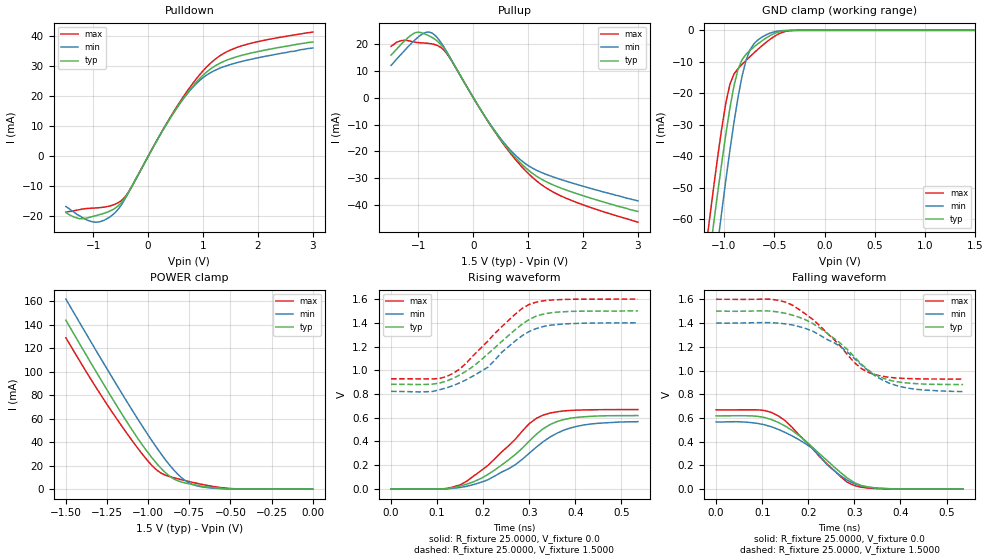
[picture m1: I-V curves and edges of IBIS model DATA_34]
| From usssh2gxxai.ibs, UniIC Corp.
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|When TDQS is enabled, NU_TDQS is a output with terminal resistance;
|When TDQS is disabled, NU_TDQS is a DM;
|   Model DATA_34
[Model]  DATA_34
Model_type I/O
Polarity   Non-Inverting
Enable   Active-High
Vinl =   0.61500000V
Vinh =   0.88500000V
Vmeas =   0.750000000V
Rref =   25.00000000
Vref =   0.75000000V
C_comp   1.6160pF   1.5840pF   1.6430pF
[Temperature Range]   25.0000   95.0000   -40.0
[Voltage Range]   1.5000V   1.4000V   1.6000V
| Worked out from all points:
|   slope of the pulldown table from 0 to 0.225 V, typ, clamps not added: 30.8 ohm
|   slope of the pullup table from 0 to 0.225 V, typ, clamps not added: 30.4 ohm
|   GND clamp passes 1 mA (typ) near -0.50 V on its own axis
|   POWER clamp passes 1 mA (typ) near -0.58 V on its own axis
|   rising waveform, R_fixture 25.0000, V_fixture 0.0: 20-80 % time 115ps typ, 125ps min, 108ps max; typ from 0 V to 0.618 V
|   rising waveform, R_fixture 25.0000, V_fixture 1.5000: 20-80 % time 113ps typ, 111ps min, 104ps max; typ from 0.881 V to 1.5 V
|   falling waveform, R_fixture 25.0000, V_fixture 0.0: 20-80 % time 110ps typ, 107ps min, 101ps max; typ from 0.618 V to 0 V
|   falling waveform, R_fixture 25.0000, V_fixture 1.5000: 20-80 % time 112ps typ, 122ps min, 104ps max; typ from 1.5 V to 0.882 V
[Pulldown]
|Voltage   I(typ)   I(min)   I(max)
-1.5V     -18.7mA    -16.7mA    -18.6mA
-1.25V    -20.76mA   -19.8mA    -17.76mA
-1V       -19.96mA   -21.85mA   -17.24mA
-800mV    -18.94mA   -21.24mA   -16.9mA
-600mV    -17.23mA   -18.69mA   -15.92mA
-350mV    -11.62mA   -11.84mA   -11.64mA
200mV     6.523mA    6.58mA     6.641mA
600mV     18.16mA    18.1mA     18.7mA
950mV     26.07mA    25.39mA    27.37mA
1.25V     30.38mA    28.86mA    32.68mA
1.8V      34.01mA    31.95mA    37.23mA
3V        38mA       36mA       41.3mA
[Pullup]
|Voltage   I(typ)   I(min)   I(max)
-1.5V     15.8mA     12mA       19.1mA
-1.3V     20.21mA    16.5mA     21.26mA
-1.05V    24.23mA    21.76mA    20.6mA
-900mV    23.84mA    24.02mA    20.34mA
-750mV    22.38mA    24mA       20mA
-500mV    17.27mA    17.66mA    16.85mA
300mV     -9.744mA   -9.622mA   -9.868mA
600mV     -18.24mA   -17.74mA   -18.65mA
850mV     -24.07mA   -22.95mA   -24.94mA
1.2V      -29.82mA   -27.44mA   -31.71mA
1.55V     -33.24mA   -30.13mA   -36.08mA
3V        -42.3mA    -38.4mA    -46.3mA
[GND_clamp]
|Voltage   I(typ)   I(min)   I(max)
-1.5V     -169mA     -189.1mA   -154.5mA
-1.18V    -80.93mA   -99.12mA   -69.3mA
-1.14V    -70.71mA   -88.3mA    -59.14mA
-1.1V     -60.74mA   -77.66mA   -49.21mA
-1.06V    -51.03mA   -67.22mA   -39.64mA
-1.02V    -41.65mA   -57.06mA   -30.7mA
-940mV    -24.55mA   -37.9mA    -17.05mA
-860mV    -12.39mA   -21.26mA   -12.14mA
-740mV    -6.329mA   -6.125mA   -8.307mA
-620mV    -3.273mA   -2.113mA   -4.841mA
-340mV    -36.93uA   -13.99uA   -106.5uA
1.5V      4.577nA    23.6nA     3.423nA
[POWER_clamp]
|Voltage   I(typ)   I(min)   I(max)
-1.5V     143.7mA    161.7mA    128.8mA
-1.26V    86.77mA    104.6mA    74.21mA
-1.12V    55.19mA    72.34mA    45.66mA
-1.02V    34.59mA    50.23mA    27.06mA
-940mV    20.5mA     33.6mA     15.4mA
-880mV    12.18mA    22.27mA    11.15mA
-840mV    8.415mA    15.63mA    9.537mA
-780mV    5.408mA    7.848mA    7.429mA
-700mV    3.206mA    2.693mA    4.858mA
-600mV    1.29mA     794.5uA    2.191mA
-440mV    104.5uA    65.08uA    176.8uA
0V        4.577nA    6.249nA    4.189nA
[Ramp]
| variable   typ   min   max
dV/dt_r  0.3707/0.1151n   0.3398/0.1312n   0.4011/0.1080n
dV/dt_f  0.3712/0.1121n   0.3468/0.1264n   0.4034/0.1038n
R_load = 25.0000
[Rising Waveform]
R_fixture= 25.0000
V_fixture= 0.0
V_fixture_min= 0.0
V_fixture_max= 0.0
|time   V(typ)   V(min)   V(max)
0s        0V         0V         0V
105ps     -1.852mV   -2.54mV    -1.884mV
150ps     23.49mV    11.68mV    33.6mV
195ps     87.14mV    55.34mV    152.4mV
255ps     244.2mV    168.8mV    362mV
300ps     402mV      300.1mV    549.6mV
330ps     505.8mV    396.8mV    621.6mV
360ps     566.8mV    468.6mV    649.5mV
405ps     603.3mV    528.8mV    663.9mV
536ps     617.9mV    566.4mV    668.5mV
[Rising Waveform]
R_fixture= 25.0000
V_fixture= 1.5000
V_fixture_min= 1.4000
V_fixture_max= 1.6000
|time   V(typ)   V(min)   V(max)
0s        881.4mV    822mV      927.8mV
105ps     891.6mV    835.6mV    930.8mV
135ps     932.4mV    870.7mV    974.6mV
180ps     1.038V     955.3mV    1.13V
210ps     1.137V     1.025V     1.245V
270ps     1.343V     1.248V     1.474V
285ps     1.39V      1.292V     1.522V
315ps     1.456V     1.351V     1.574V
375ps     1.493V     1.39V      1.597V
536ps     1.5V       1.4V       1.6V
[Falling Waveform]
R_fixture= 25.0000
V_fixture= 0.0
V_fixture_min= 0.0
V_fixture_max= 0.0
|time   V(typ)   V(min)   V(max)
0s        617.9mV    566.4mV    668.5mV
105ps     604mV      542.3mV    663mV
135ps     561.8mV    503.8mV    617.1mV
165ps     494.7mV    448.6mV    520.5mV
210ps     350mV      341.6mV    337.5mV
240ps     243.9mV    208.2mV    215.6mV
285ps     92.81mV    74.32mV    57.7mV
300ps     55.27mV    45.68mV    30.7mV
360ps     5.644mV    6.888mV    3.014mV
536ps     0V         0V         0V
[Falling Waveform]
R_fixture= 25.0000
V_fixture= 1.5000
V_fixture_min= 1.4000
V_fixture_max= 1.6000
|time   V(typ)   V(min)   V(max)
0s        1.5V       1.4V       1.6V
120ps     1.5V       1.403V     1.6V
165ps     1.467V     1.384V     1.552V
210ps     1.395V     1.331V     1.43V
270ps     1.228V     1.201V     1.204V
315ps     1.054V     1.047V     1.017V
345ps     965.9mV    955.6mV    964.2mV
375ps     919.3mV    894.4mV    943mV
420ps     892.9mV    849mV      931.7mV
536ps     881.5mV    822.1mV    927.7mV
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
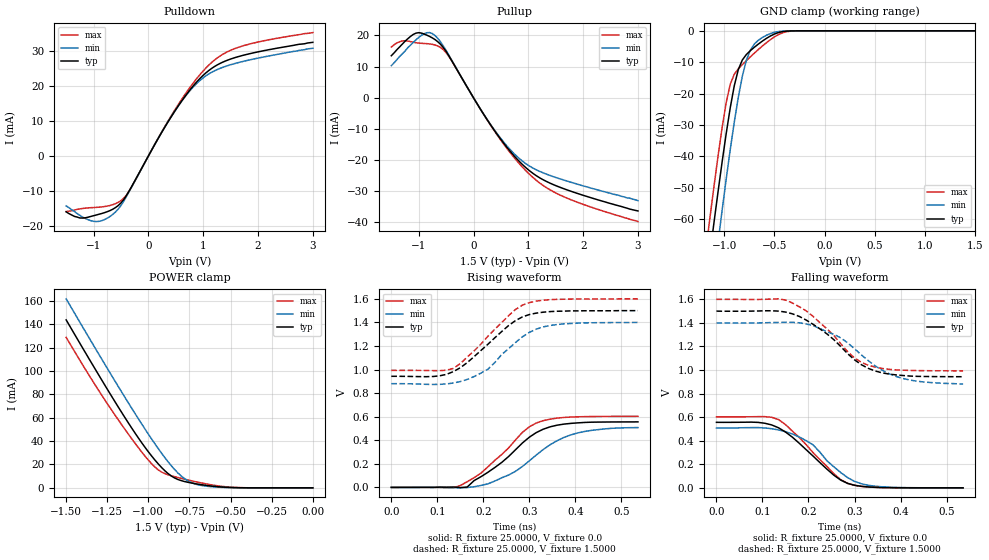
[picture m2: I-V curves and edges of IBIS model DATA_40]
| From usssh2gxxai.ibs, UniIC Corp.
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|   Model DATA_40
[Model]  DATA_40
Model_type I/O
Polarity   Non-Inverting
Enable   Active-High
Vinl =   0.61500000V
Vinh =   0.88500000V
Vmeas =   0.750000000V
Rref =   25.00000000
Vref =   0.75000000V
C_comp   1.6160pF   1.5840pF   1.6430pF
[Temperature Range]   25.0000   95.0000   -40.0
[Voltage Range]   1.5000V   1.4000V   1.6000V
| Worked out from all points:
|   slope of the pulldown table from 0 to 0.225 V, typ, clamps not added: 35.8 ohm
|   slope of the pullup table from 0 to 0.225 V, typ, clamps not added: 35.3 ohm
|   GND clamp passes 1 mA (typ) near -0.50 V on its own axis
|   POWER clamp passes 1 mA (typ) near -0.58 V on its own axis
|   rising waveform, R_fixture 25.0000, V_fixture 0.0: 20-80 % time 104ps typ, 113ps min, 95.2ps max; typ from 0 V to 0.556 V
|   rising waveform, R_fixture 25.0000, V_fixture 1.5000: 20-80 % time 96.8ps typ, 90.8ps min, 93.6ps max; typ from 0.943 V to 1.5 V
|   falling waveform, R_fixture 25.0000, V_fixture 0.0: 20-80 % time 94.1ps typ, 87.6ps min, 90.3ps max; typ from 0.556 V to 0 V
|   falling waveform, R_fixture 25.0000, V_fixture 1.5000: 20-80 % time 102ps typ, 109ps min, 94.3ps max; typ from 1.5 V to 0.943 V
[Pulldown]
|Voltage   I(typ)   I(min)   I(max)
-1.5V     -16mA      -14.3mA    -15.9mA
-1.25V    -17.76mA   -17mA      -15.16mA
-1V       -17.11mA   -18.73mA   -14.78mA
-800mV    -16.23mA   -18.22mA   -14.49mA
-600mV    -14.78mA   -16.05mA   -13.66mA
-350mV    -9.992mA   -10.19mA   -10mA
200mV     5.609mA    5.658mA    5.711mA
600mV     15.61mA    15.56mA    16.08mA
900mV     21.57mA    21.09mA    22.57mA
1.25V     26.07mA    24.76mA    28.05mA
1.75V     28.97mA    27.21mA    31.71mA
3V        32.6mA     30.9mA     35.4mA
[Pullup]
|Voltage   I(typ)   I(min)   I(max)
-1.5V     13.5mA     10.3mA     16.3mA
-1.3V     17.21mA    14.1mA     18.26mA
-1.05V    20.75mA    18.62mA    17.66mA
-900mV    20.45mA    20.57mA    17.43mA
-750mV    19.21mA    20.61mA    17.15mA
-500mV    14.86mA    15.19mA    14.48mA
300mV     -8.378mA   -8.272mA   -8.485mA
600mV     -15.67mA   -15.24mA   -16.03mA
900mV     -21.53mA   -20.42mA   -22.38mA
1.2V      -25.59mA   -23.55mA   -27.23mA
1.6V      -28.86mA   -26.12mA   -31.37mA
3V        -36.3mA    -33mA      -39.7mA
[GND_clamp]
|Voltage   I(typ)   I(min)   I(max)
-1.5V     -169mA     -189.1mA   -154.5mA
-1.18V    -80.93mA   -99.12mA   -69.3mA
-1.14V    -70.71mA   -88.3mA    -59.14mA
-1.1V     -60.74mA   -77.66mA   -49.21mA
-1.06V    -51.03mA   -67.22mA   -39.64mA
-1.02V    -41.65mA   -57.06mA   -30.7mA
-940mV    -24.55mA   -37.9mA    -17.05mA
-860mV    -12.39mA   -21.26mA   -12.14mA
-740mV    -6.329mA   -6.125mA   -8.307mA
-620mV    -3.273mA   -2.113mA   -4.841mA
-340mV    -36.93uA   -13.99uA   -106.5uA
1.5V      4.577nA    23.6nA     3.423nA
[POWER_clamp]
|Voltage   I(typ)   I(min)   I(max)
-1.5V     143.7mA    161.7mA    128.8mA
-1.26V    86.77mA    104.6mA    74.21mA
-1.12V    55.19mA    72.34mA    45.66mA
-1.02V    34.59mA    50.23mA    27.06mA
-940mV    20.5mA     33.6mA     15.4mA
-880mV    12.18mA    22.27mA    11.15mA
-840mV    8.415mA    15.63mA    9.537mA
-780mV    5.408mA    7.848mA    7.429mA
-700mV    3.206mA    2.693mA    4.858mA
-600mV    1.29mA     794.5uA    2.191mA
-440mV    104.5uA    65.08uA    176.8uA
0V        4.577nA    6.249nA    4.189nA
[Ramp]
| variable   typ   min   max
dV/dt_r  0.3336/0.1041n   0.3046/0.1129n   0.3619/95.2449p
dV/dt_f  0.3342/0.1019n   0.3119/0.1089n   0.3642/94.3055p
R_load = 25.0000
[Rising Waveform]
R_fixture= 25.0000
V_fixture= 0.0
V_fixture_min= 0.0
V_fixture_max= 0.0
|time   V(typ)   V(min)   V(max)
0s        0V         0V         0V
135ps     3.196mV    -2.504mV   -2.501mV
165ps     3.18mV     -1.232mV   48.34mV
195ps     91.04mV    16.64mV    121.8mV
255ps     262.5mV    105.1mV    335.4mV
300ps     426.3mV    225.7mV    514.6mV
330ps     493.7mV    321mV      566.4mV
360ps     527.9mV    395.6mV    588.1mV
405ps     547.6mV    462.1mV    599.1mV
536ps     556mV      507.7mV    603.1mV
[Rising Waveform]
R_fixture= 25.0000
V_fixture= 1.5000
V_fixture_min= 1.4000
V_fixture_max= 1.6000
|time   V(typ)   V(min)   V(max)
0s        943.1mV    880.2mV    993mV
90.91ps   941.1mV    873.7mV    991.1mV
135ps     982.9mV    885.9mV    1.01V
165ps     1.059V     916.3mV    1.106V
210ps     1.215V     1.003V     1.283V
270ps     1.416V     1.23V      1.51V
300ps     1.467V     1.316V     1.568V
330ps     1.487V     1.362V     1.588V
375ps     1.496V     1.388V     1.597V
536ps     1.5V       1.4V       1.6V
[Falling Waveform]
R_fixture= 25.0000
V_fixture= 0.0
V_fixture_min= 0.0
V_fixture_max= 0.0
|time   V(typ)   V(min)   V(max)
0s        556mV      507.6mV    603.1mV
90.91ps   555.5mV    511.5mV    604.3mV
135ps     509.5mV    491.6mV    579.2mV
165ps     430mV      457.4mV    481.7mV
210ps     269.6mV    364.7mV    298.6mV
240ps     159.1mV    230.3mV    182mV
270ps     66mV       129.8mV    69.07mV
285ps     37.64mV    87.05mV    38.33mV
345ps     4.435mV    13.7mV     4.247mV
536ps     0V         0V         0V
[Falling Waveform]
R_fixture= 25.0000
V_fixture= 1.5000
V_fixture_min= 1.4000
V_fixture_max= 1.6000
|time   V(typ)   V(min)   V(max)
0s        1.5V       1.4V       1.6V
135ps     1.5V       1.404V     1.604V
165ps     1.477V     1.405V     1.569V
195ps     1.424V     1.391V     1.502V
255ps     1.258V     1.303V     1.293V
300ps     1.087V     1.181V     1.103V
330ps     1.014V     1.079V     1.04V
360ps     976.2mV    998.9mV    1.013V
405ps     953.6mV    928.4mV    998.7mV
536ps     943.1mV    880.4mV    993mV
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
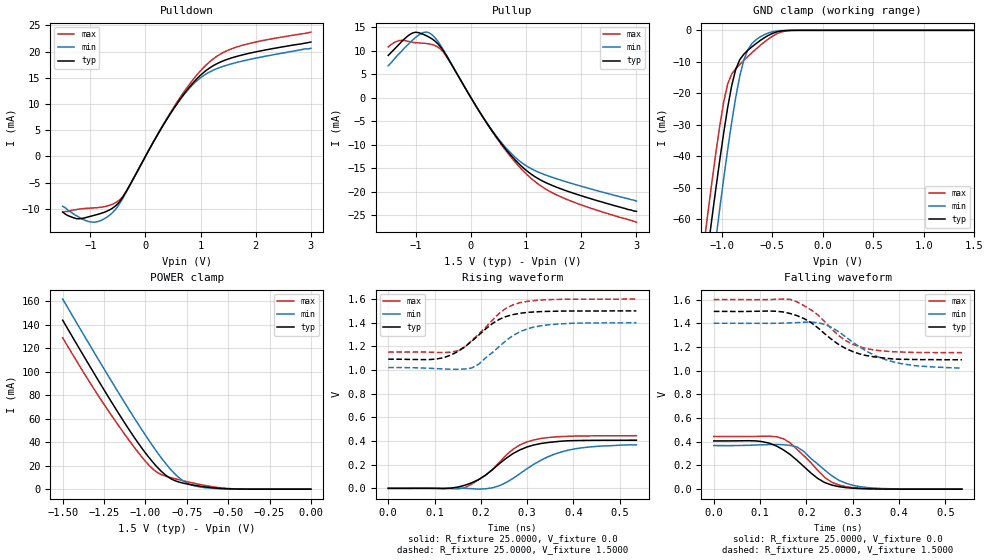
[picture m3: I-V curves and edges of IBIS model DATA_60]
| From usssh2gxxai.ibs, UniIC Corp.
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|   Model DATA_60
[Model]  DATA_60
Model_type I/O
Polarity   Non-Inverting
Enable   Active-High
Vinl =   0.61500000V
Vinh =   0.88500000V
Vmeas =   0.750000000V
Rref =   25.00000000
Vref =   0.75000000V
C_comp   1.6160pF   1.5840pF   1.6430pF
[Temperature Range]   25.0000   95.0000   -40.0
[Voltage Range]   1.5000V   1.4000V   1.6000V
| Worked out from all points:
|   slope of the pulldown table from 0 to 0.225 V, typ, clamps not added: 53.4 ohm
|   slope of the pullup table from 0 to 0.225 V, typ, clamps not added: 52.6 ohm
|   GND clamp passes 1 mA (typ) near -0.50 V on its own axis
|   POWER clamp passes 1 mA (typ) near -0.58 V on its own axis
|   rising waveform, R_fixture 25.0000, V_fixture 0.0: 20-80 % time 86.5ps typ, 98.3ps min, 78.4ps max; typ from 0 V to 0.407 V
|   rising waveform, R_fixture 25.0000, V_fixture 1.5000: 20-80 % time 78.8ps typ, 76.1ps min, 72.1ps max; typ from 1.09 V to 1.5 V
|   falling waveform, R_fixture 25.0000, V_fixture 0.0: 20-80 % time 75.8ps typ, 70.4ps min, 68.8ps max; typ from 0.407 V to 0 V
|   falling waveform, R_fixture 25.0000, V_fixture 1.5000: 20-80 % time 88.4ps typ, 97.1ps min, 79.8ps max; typ from 1.5 V to 1.09 V
[Pulldown]
|Voltage   I(typ)   I(min)   I(max)
-1.5V     -10.6mA    -9.5mA     -10.6mA
-1.25V    -11.86mA   -11.3mA    -10.13mA
-1V       -11.42mA   -12.48mA   -9.85mA
-800mV    -10.84mA   -12.17mA   -9.67mA
-600mV    -9.882mA   -10.74mA   -9.123mA
-350mV    -6.704mA   -6.838mA   -6.711mA
200mV     3.763mA    3.796mA    3.832mA
550mV     9.696mA    9.684mA    9.971mA
900mV     14.44mA    14.11mA    15.12mA
1.25V     17.42mA    16.53mA    18.75mA
1.75V     19.33mA    18.16mA    21.16mA
3V        21.8mA     20.6mA     23.7mA
[Pullup]
|Voltage   I(typ)   I(min)   I(max)
-1.5V     9mA        6.8mA      10.8mA
-1.3V     11.41mA    9.4mA      12.16mA
-1.05V    13.82mA    12.36mA    11.78mA
-900mV    13.65mA    13.69mA    11.62mA
-750mV    12.84mA    13.77mA    11.44mA
-600mV    11.47mA    12.01mA    10.78mA
-450mV    9.041mA    9.198mA    8.905mA
300mV     -5.62mA    -5.548mA   -5.692mA
850mV     -13.84mA   -13.18mA   -14.35mA
1.2V      -17.1mA    -15.73mA   -18.21mA
1.55V     -19.04mA   -17.25mA   -20.68mA
3V        -24.2mA    -22mA      -26.5mA
[GND_clamp]
|Voltage   I(typ)   I(min)   I(max)
-1.5V     -169mA     -189.1mA   -154.5mA
-1.18V    -80.93mA   -99.12mA   -69.3mA
-1.14V    -70.71mA   -88.3mA    -59.14mA
-1.1V     -60.74mA   -77.66mA   -49.21mA
-1.06V    -51.03mA   -67.22mA   -39.64mA
-1.02V    -41.65mA   -57.06mA   -30.7mA
-940mV    -24.55mA   -37.9mA    -17.05mA
-860mV    -12.39mA   -21.26mA   -12.14mA
-740mV    -6.329mA   -6.125mA   -8.307mA
-620mV    -3.273mA   -2.113mA   -4.841mA
-340mV    -36.93uA   -13.99uA   -106.5uA
1.5V      4.577nA    23.6nA     3.423nA
[POWER_clamp]
|Voltage   I(typ)   I(min)   I(max)
-1.5V     143.7mA    161.7mA    128.8mA
-1.26V    86.77mA    104.6mA    74.21mA
-1.12V    55.19mA    72.34mA    45.66mA
-1.02V    34.59mA    50.23mA    27.06mA
-940mV    20.5mA     33.6mA     15.4mA
-880mV    12.18mA    22.27mA    11.15mA
-840mV    8.415mA    15.63mA    9.537mA
-780mV    5.408mA    7.848mA    7.429mA
-700mV    3.206mA    2.693mA    4.858mA
-600mV    1.29mA     794.5uA    2.191mA
-440mV    104.5uA    65.08uA    176.8uA
0V        4.577nA    6.249nA    4.189nA
[Ramp]
| variable   typ   min   max
dV/dt_r  0.2442/86.5366p   0.2207/98.3857p   0.2669/78.4595p
dV/dt_f  0.2448/88.3671p   0.2280/97.6364p   0.2688/79.7930p
R_load = 25.0000
[Rising Waveform]
R_fixture= 25.0000
V_fixture= 0.0
V_fixture_min= 0.0
V_fixture_max= 0.0
|time   V(typ)   V(min)   V(max)
0s        0V         0V         0V
120ps     -2.381mV   528.8uV    -193.2uV
165ps     25.57mV    122.5uV    4.749mV
195ps     73.7mV     -6.902mV   72.87mV
225ps     157.9mV    4.509mV    158.5mV
270ps     295.1mV    85.55mV    331.9mV
315ps     367.2mV    204.9mV    409.4mV
360ps     393.6mV    290.1mV    434.5mV
405ps     403.9mV    335.2mV    441.7mV
536ps     407mV      367.8mV    444.8mV
[Rising Waveform]
R_fixture= 25.0000
V_fixture= 1.5000
V_fixture_min= 1.4000
V_fixture_max= 1.6000
|time   V(typ)   V(min)   V(max)
0s        1.092V     1.021V     1.152V
105ps     1.094V     1.012V     1.149V
150ps     1.156V     1.006V     1.163V
180ps     1.242V     1.017V     1.248V
195ps     1.294V     1.048V     1.303V
240ps     1.429V     1.2V       1.481V
285ps     1.48V      1.325V     1.57V
315ps     1.491V     1.364V     1.587V
360ps     1.497V     1.387V     1.596V
536ps     1.5V       1.4V       1.6V
[Falling Waveform]
R_fixture= 25.0000
V_fixture= 0.0
V_fixture_min= 0.0
V_fixture_max= 0.0
|time   V(typ)   V(min)   V(max)
0s        407mV      367.9mV    444.9mV
105ps     400.8mV    374.5mV    446.1mV
150ps     332.6mV    375.2mV    426.3mV
180ps     242.9mV    355.8mV    335.1mV
225ps     89.18mV    210mV      156.7mV
255ps     34.49mV    112.9mV    58.62mV
285ps     13.4mV     50.27mV    21.44mV
315ps     5.146mV    21.72mV    8.508mV
360ps     1.268mV    6.211mV    1.932mV
536ps     0V         0V         0V
[Falling Waveform]
R_fixture= 25.0000
V_fixture= 1.5000
V_fixture_min= 1.4000
V_fixture_max= 1.6000
|time   V(typ)   V(min)   V(max)
0s        1.5V       1.4V       1.6V
120ps     1.503V     1.399V     1.6V
165ps     1.482V     1.403V     1.601V
195ps     1.439V     1.409V     1.548V
225ps     1.361V     1.404V     1.47V
255ps     1.262V     1.364V     1.35V
285ps     1.187V     1.284V     1.253V
330ps     1.127V     1.164V     1.186V
405ps     1.096V     1.059V     1.157V
536ps     1.092V     1.021V     1.152V
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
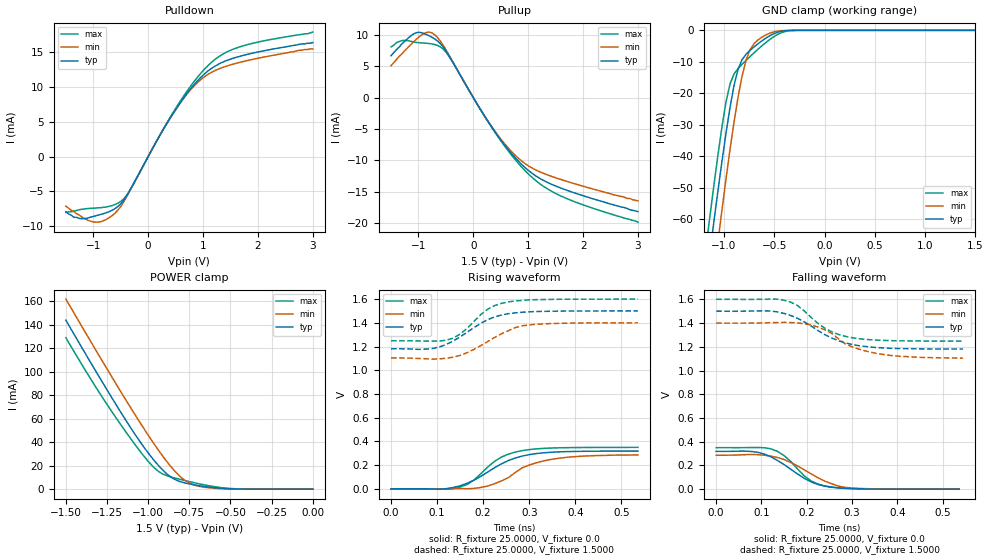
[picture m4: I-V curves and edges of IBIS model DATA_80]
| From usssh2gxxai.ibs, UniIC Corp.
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|   Model DATA_80
[Model]  DATA_80
Model_type I/O
Polarity   Non-Inverting
Enable   Active-High
Vinl =   0.61500000V
Vinh =   0.88500000V
Vmeas =   0.750000000V
Rref =   25.00000000
Vref =   0.75000000V
C_comp   1.6160pF   1.5840pF   1.6430pF
[Temperature Range]   25.0000   95.0000   -40.0
[Voltage Range]   1.5000V   1.4000V   1.6000V
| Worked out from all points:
|   slope of the pulldown table from 0 to 0.225 V, typ, clamps not added: 70.9 ohm
|   slope of the pullup table from 0 to 0.225 V, typ, clamps not added: 70 ohm
|   GND clamp passes 1 mA (typ) near -0.50 V on its own axis
|   POWER clamp passes 1 mA (typ) near -0.58 V on its own axis
|   rising waveform, R_fixture 25.0000, V_fixture 0.0: 20-80 % time 91.4ps typ, 90.7ps min, 68.8ps max; typ from 0 V to 0.318 V
|   rising waveform, R_fixture 25.0000, V_fixture 1.5000: 20-80 % time 82.5ps typ, 85.9ps min, 63ps max; typ from 1.18 V to 1.5 V
|   falling waveform, R_fixture 25.0000, V_fixture 0.0: 20-80 % time 79.1ps typ, 84.6ps min, 58.6ps max; typ from 0.318 V to 0 V
|   falling waveform, R_fixture 25.0000, V_fixture 1.5000: 20-80 % time 93.8ps typ, 90.3ps min, 74.8ps max; typ from 1.5 V to 1.18 V
[Pulldown]
|Voltage   I(typ)   I(min)   I(max)
-1.5V     -7.9mA     -7.1mA     -8mA
-1.25V    -8.86mA    -8.4mA     -7.6mA
-1V       -8.57mA    -9.35mA    -7.39mA
-800mV    -8.135mA   -9.13mA    -7.25mA
-600mV    -7.422mA   -8.068mA   -6.843mA
-350mV    -5.045mA   -5.146mA   -5.049mA
200mV     2.832mA    2.856mA    2.884mA
600mV     7.865mA    7.837mA    8.105mA
900mV     10.85mA    10.6mA     11.36mA
1.25V     13.07mA    12.41mA    14.08mA
1.8V      14.6mA     13.72mA    15.99mA
3V        16.3mA     15.4mA     17.8mA
[Pullup]
|Voltage   I(typ)   I(min)   I(max)
-1.5V     6.7mA      5.1mA      8.1mA
-1.3V     8.61mA     7mA        9.12mA
-1.05V    10.35mA    9.26mA     8.84mA
-900mV    10.25mA    10.25mA    8.72mA
-750mV    9.639mA    10.35mA    8.588mA
-600mV    8.621mA    9.028mA    8.099mA
-450mV    6.804mA    6.923mA    6.7mA
350mV     -4.882mA   -4.81mA    -4.953mA
900mV     -10.83mA   -10.26mA   -11.27mA
1.25V     -13.09mA   -11.99mA   -14mA
1.6V      -14.46mA   -13.09mA   -15.73mA
3V        -18.2mA    -16.5mA    -19.9mA
[GND_clamp]
|Voltage   I(typ)   I(min)   I(max)
-1.5V     -169mA     -189.1mA   -154.5mA
-1.18V    -80.93mA   -99.12mA   -69.3mA
-1.14V    -70.71mA   -88.3mA    -59.14mA
-1.1V     -60.74mA   -77.66mA   -49.21mA
-1.06V    -51.03mA   -67.22mA   -39.64mA
-1.02V    -41.65mA   -57.06mA   -30.7mA
-940mV    -24.55mA   -37.9mA    -17.05mA
-860mV    -12.39mA   -21.26mA   -12.14mA
-740mV    -6.329mA   -6.125mA   -8.307mA
-620mV    -3.273mA   -2.113mA   -4.841mA
-340mV    -36.93uA   -13.99uA   -106.5uA
1.5V      4.577nA    23.6nA     3.423nA
[POWER_clamp]
|Voltage   I(typ)   I(min)   I(max)
-1.5V     143.7mA    161.7mA    128.8mA
-1.26V    86.77mA    104.6mA    74.21mA
-1.12V    55.19mA    72.34mA    45.66mA
-1.02V    34.59mA    50.23mA    27.06mA
-940mV    20.5mA     33.6mA     15.4mA
-880mV    12.18mA    22.27mA    11.15mA
-840mV    8.415mA    15.63mA    9.537mA
-780mV    5.408mA    7.848mA    7.429mA
-700mV    3.206mA    2.693mA    4.858mA
-600mV    1.29mA     794.5uA    2.191mA
-440mV    104.5uA    65.08uA    176.8uA
0V        4.577nA    6.249nA    4.189nA
[Ramp]
| variable   typ   min   max
dV/dt_r  0.1912/91.4560p   0.1717/0.1057n   0.2099/68.8004p
dV/dt_f  0.1914/93.7667p   0.1776/0.1053n   0.2112/74.8340p
R_load = 25.0000
[Rising Waveform]
R_fixture= 25.0000
V_fixture= 0.0
V_fixture_min= 0.0
V_fixture_max= 0.0
|time   V(typ)   V(min)   V(max)
0s        0V         0V         0V
105ps     -2.434mV   6.45uV     -600.2uV
150ps     25.97mV    3.571mV    16.58mV
180ps     73.35mV    3.869mV    74.68mV
225ps     178.9mV    43.53mV    233mV
255ps     239.2mV    95.42mV    292.8mV
285ps     276.7mV    178.3mV    322.6mV
330ps     303.6mV    234.7mV    341.1mV
375ps     313.4mV    263.4mV    346.9mV
536ps     318.5mV    286.1mV    349.9mV
[Rising Waveform]
R_fixture= 25.0000
V_fixture= 1.5000
V_fixture_min= 1.4000
V_fixture_max= 1.6000
|time   V(typ)   V(min)   V(max)
0s        1.181V     1.104V     1.248V
90.91ps   1.184V     1.094V     1.246V
135ps     1.247V     1.11V      1.271V
165ps     1.32V      1.148V     1.352V
210ps     1.426V     1.242V     1.515V
225ps     1.45V      1.277V     1.545V
255ps     1.477V     1.334V     1.576V
285ps     1.489V     1.375V     1.589V
330ps     1.496V     1.391V     1.596V
536ps     1.5V       1.4V       1.6V
[Falling Waveform]
R_fixture= 25.0000
V_fixture= 0.0
V_fixture_min= 0.0
V_fixture_max= 0.0
|time   V(typ)   V(min)   V(max)
0s        318.5mV    285.8mV    349.9mV
75.76ps   318.4mV    292mV      350.6mV
120ps     274mV      279mV      340.8mV
150ps     207.1mV    249.4mV    282.5mV
195ps     90.47mV    161.8mV    109.9mV
210ps     60.43mV    128.1mV    68.31mV
240ps     25.28mV    67.16mV    26.77mV
270ps     10.66mV    26.07mV    10.99mV
300ps     4.654mV    9.695mV    4.529mV
536ps     0V         0V         0V
[Falling Waveform]
R_fixture= 25.0000
V_fixture= 1.5000
V_fixture_min= 1.4000
V_fixture_max= 1.6000
|time   V(typ)   V(min)   V(max)
0s        1.5V       1.4V       1.6V
120ps     1.501V     1.403V     1.602V
165ps     1.463V     1.404V     1.576V
180ps     1.439V     1.401V     1.546V
210ps     1.374V     1.383V     1.446V
240ps     1.302V     1.342V     1.356V
270ps     1.251V     1.266V     1.304V
300ps     1.22V      1.2V       1.276V
390ps     1.186V     1.125V     1.251V
545ps     1.181V     1.104V     1.248V
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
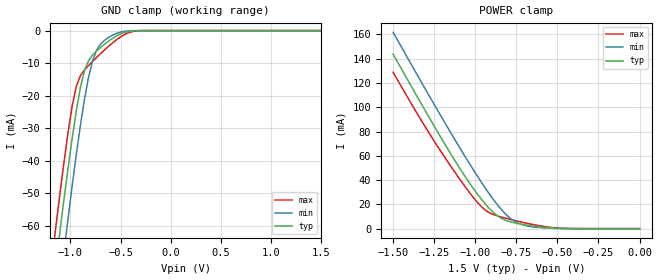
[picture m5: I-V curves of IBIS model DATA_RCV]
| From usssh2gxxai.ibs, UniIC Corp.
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|   Model DATA_RCV
[Model]  DATA_RCV
Model_type Input
Polarity   Non-Inverting
Vinl =   0.60000000V
Vinh =   0.90000000V
C_comp   1.6160pF   1.5840pF   1.6430pF
[Temperature Range]   25.0000   95.0000   -40.0
[Voltage Range]   1.5000V   1.4000V   1.6000V
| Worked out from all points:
|   GND clamp passes 1 mA (typ) near -0.50 V on its own axis
|   POWER clamp passes 1 mA (typ) near -0.58 V on its own axis
[GND_clamp]
|Voltage   I(typ)   I(min)   I(max)
-1.5V     -169mA     -189.1mA   -154.5mA
-1.18V    -80.93mA   -99.12mA   -69.3mA
-1.14V    -70.71mA   -88.3mA    -59.14mA
-1.1V     -60.74mA   -77.66mA   -49.21mA
-1.06V    -51.03mA   -67.22mA   -39.64mA
-1.02V    -41.65mA   -57.06mA   -30.7mA
-940mV    -24.55mA   -37.9mA    -17.05mA
-860mV    -12.39mA   -21.26mA   -12.14mA
-740mV    -6.329mA   -6.125mA   -8.307mA
-620mV    -3.273mA   -2.113mA   -4.841mA
-340mV    -36.93uA   -13.99uA   -106.5uA
1.5V      4.577nA    23.6nA     3.423nA
[POWER_clamp]
|Voltage   I(typ)   I(min)   I(max)
-1.5V     143.7mA    161.7mA    128.8mA
-1.26V    86.77mA    104.6mA    74.21mA
-1.12V    55.19mA    72.34mA    45.66mA
-1.02V    34.59mA    50.23mA    27.06mA
-940mV    20.5mA     33.6mA     15.4mA
-880mV    12.18mA    22.27mA    11.15mA
-840mV    8.415mA    15.63mA    9.537mA
-780mV    5.408mA    7.848mA    7.429mA
-700mV    3.206mA    2.693mA    4.858mA
-600mV    1.29mA     794.5uA    2.191mA
-440mV    104.5uA    65.08uA    176.8uA
0V        4.577nA    6.249nA    4.189nA
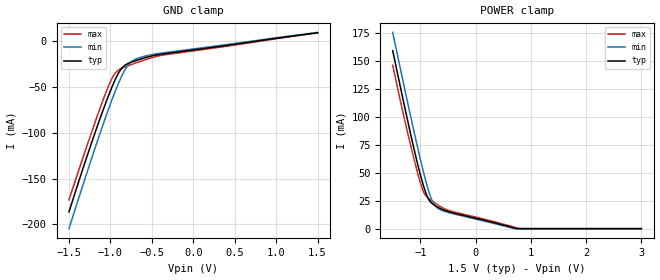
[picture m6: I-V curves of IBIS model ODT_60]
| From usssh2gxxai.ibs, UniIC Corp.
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|   Model ODT_60
[Model]  ODT_60
Model_type Input
Polarity   Non-Inverting
Vinl =   0.60000000V
Vinh =   0.90000000V
C_comp   1.6160pF   1.5840pF   1.6430pF
[Temperature Range]   25.0000   95.0000   -40.0
[Voltage Range]   1.5000V   1.4000V   1.6000V
[GND_clamp]
|Voltage   I(typ)   I(min)   I(max)
-1.5V     -186.4mA   -204.7mA   -173.2mA
-1.3V     -130.5mA   -148.3mA   -118.8mA
-1.14V    -88.18mA   -104.6mA   -76.93mA
-1.06V    -68.27mA   -83.56mA   -57.26mA
-980mV    -49.72mA   -63.56mA   -40.32mA
-940mV    -41.41mA   -54.16mA   -34.42mA
-860mV    -29mA      -37.33mA   -29.33mA
-780mV    -23.92mA   -25.21mA   -26.53mA
-740mV    -22.53mA   -21.73mA   -25.19mA
-620mV    -18.96mA   -17.07mA   -21.32mA
-380mV    -13.97mA   -12.83mA   -15.29mA
1.5V      9.293mA    9.746mA    9.152mA
[POWER_clamp]
|Voltage   I(typ)   I(min)   I(max)
-1.5V     159mA      175.3mA    146.1mA
-1.36V    126.3mA    142.6mA    113.9mA
-1.22V    94.37mA    110.4mA    83.57mA
-1.08V    64mA       79.21mA    55.47mA
-980mV    44.62mA    58.02mA    37.89mA
-920mV    34.72mA    46.14mA    30.79mA
-860mV    27.17mA    35.41mA    27.47mA
-780mV    22.19mA    24.37mA    24.48mA
-700mV    19.64mA    18.87mA    21.74mA
-460mV    14.73mA    14.05mA    15.81mA
749.7mV   0A         NA         NA
3V        0A         0A         0A
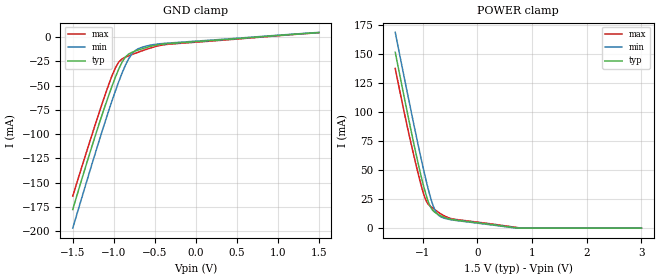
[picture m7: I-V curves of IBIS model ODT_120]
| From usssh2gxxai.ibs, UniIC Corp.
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|   Model ODT_120
[Model]  ODT_120
Model_type Input
Polarity   Non-Inverting
Vinl =   0.60000000V
Vinh =   0.90000000V
C_comp   1.6160pF   1.5840pF   1.6430pF
[Temperature Range]   25.0000   95.0000   -40.0
[Voltage Range]   1.5000V   1.4000V   1.6000V
[GND_clamp]
|Voltage   I(typ)   I(min)   I(max)
-1.5V     -177.7mA   -196.9mA   -163.9mA
-1.3V     -121.7mA   -140.3mA   -109.7mA
-1.14V    -79.45mA   -96.44mA   -68.04mA
-1.06V    -59.66mA   -75.39mA   -48.46mA
-980mV    -41.23mA   -55.41mA   -31.59mA
-940mV    -32.98mA   -46.03mA   -25.74mA
-860mV    -20.7mA    -29.3mA    -20.74mA
-780mV    -15.76mA   -17.33mA   -18.04mA
-740mV    -14.44mA   -13.93mA   -16.75mA
-580mV    -10.15mA   -8.765mA   -11.95mA
-340mV    -6.759mA   -6.189mA   -7.411mA
1.5V      4.649mA    4.877mA    4.578mA
[POWER_clamp]
|Voltage   I(typ)   I(min)   I(max)
-1.5V     151.4mA    168.5mA    137.4mA
-1.34V    113.6mA    130.7mA    100.6mA
-1.22V    85.96mA    102.9mA    74.69mA
-1.08V    55.33mA    71.28mA    46.73mA
-980mV    35.92mA    49.88mA    29.24mA
-920mV    26.09mA    37.91mA    22.17mA
-860mV    18.63mA    27.12mA    18.89mA
-780mV    13.81mA    16.11mA    15.96mA
-700mV    11.43mA    10.79mA    13.3mA
-440mV    7.293mA    6.937mA    7.861mA
749.8mV   0A         NA         NA
3V        0A         0A         0A
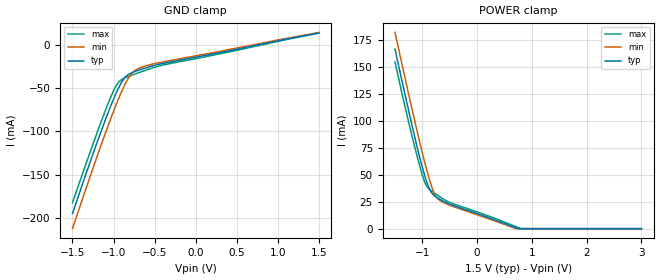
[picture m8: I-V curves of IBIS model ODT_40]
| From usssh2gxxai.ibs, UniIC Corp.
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|   Model ODT_40
[Model]  ODT_40
Model_type Input
Polarity   Non-Inverting
Vinl =   0.60000000V
Vinh =   0.90000000V
C_comp   1.6160pF   1.5840pF   1.6430pF
[Temperature Range]   25.0000   95.0000   -40.0
[Voltage Range]   1.5000V   1.4000V   1.6000V
[GND_clamp]
|Voltage   I(typ)   I(min)   I(max)
-1.5V     -195.1mA   -212.5mA   -182.6mA
-1.34V    -150.3mA   -167.5mA   -138.7mA
-1.14V    -96.9mA    -112.7mA   -85.81mA
-1.06V    -76.87mA   -91.72mA   -66.06mA
-980mV    -58.2mA    -71.71mA   -49.03mA
-940mV    -49.83mA   -62.28mA   -43.1mA
-860mV    -37.29mA   -45.35mA   -37.92mA
-780mV    -32.08mA   -33.09mA   -35.01mA
-740mV    -30.62mA   -29.51mA   -33.61mA
-660mV    -28.02mA   -25.76mA   -30.87mA
-460mV    -22.5mA    -20.68mA   -24.67mA
1.5V      13.93mA    14.61mA    13.72mA
[POWER_clamp]
|Voltage   I(typ)   I(min)   I(max)
-1.5V     166.7mA    182.1mA    154.7mA
-1.32V    125.3mA    140.7mA    113.9mA
-1.2V     98.37mA    113.5mA    88.28mA
-1.06V    68.61mA    82.85mA    60.4mA
-980mV    53.32mA    66.16mA    46.55mA
-920mV    43.34mA    54.38mA    39.41mA
-860mV    35.69mA    43.7mA     36.05mA
-780mV    30.57mA    32.62mA    33mA
-700mV    27.84mA    26.94mA    30.17mA
-460mV    21.99mA    20.99mA    23.56mA
749.7mV   0A         NA         NA
3V        0A         0A         0A
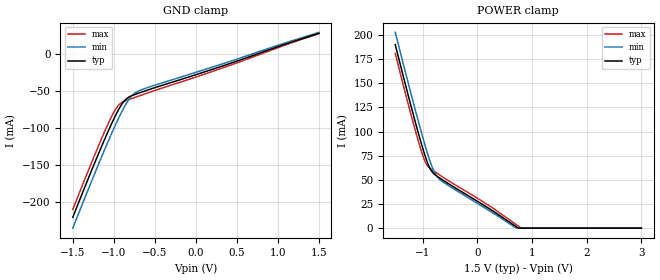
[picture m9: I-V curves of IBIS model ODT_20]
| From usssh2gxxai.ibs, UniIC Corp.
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|   Model ODT_20
[Model]  ODT_20
Model_type Input
Polarity   Non-Inverting
Vinl =   0.60000000V
Vinh =   0.90000000V
C_comp   1.6160pF   1.5840pF   1.6430pF
[Temperature Range]   25.0000   95.0000   -40.0
[Voltage Range]   1.5000V   1.4000V   1.6000V
[GND_clamp]
|Voltage   I(typ)   I(min)   I(max)
-1.5V     -221.3mA   -235.9mA   -210.6mA
-1.3V     -165.8mA   -180.4mA   -155.1mA
-1.14V    -123mA     -137.1mA   -112.4mA
-1.06V    -102.6mA   -116.2mA   -92.41mA
-980mV    -83.58mA   -96.13mA   -75.13mA
-940mV    -75.02mA   -86.6mA    -69.07mA
-860mV    -62.11mA   -69.36mA   -63.61mA
-780mV    -56.5mA    -56.64mA   -60.4mA
-740mV    -54.81mA   -52.79mA   -58.83mA
-540mV    -47.2mA    -43.82mA   -51.04mA
260mV     -18.77mA   -15.77mA   -21.57mA
1.5V      27.81mA    29.14mA    27.4mA
[POWER_clamp]
|Voltage   I(typ)   I(min)   I(max)
-1.5V     189.9mA    202.6mA    180.8mA
-1.18V    119.6mA    132.2mA    110.6mA
-1.06V    94.72mA    106.8mA    86.52mA
-980mV    79.37mA    90.63mA    72.48mA
-920mV    69.16mA    79.12mA    65.23mA
-880mV    63.51mA    71.94mA    62.69mA
-840mV    59.32mA    65.37mA    60.92mA
-760mV    54.75mA    55.28mA    57.74mA
-680mV    51.59mA    50.03mA    54.65mA
200mV     20.8mA     18.75mA    23.8mA
749.7mV   0A         NA         NA
3V        0A         0A         0A
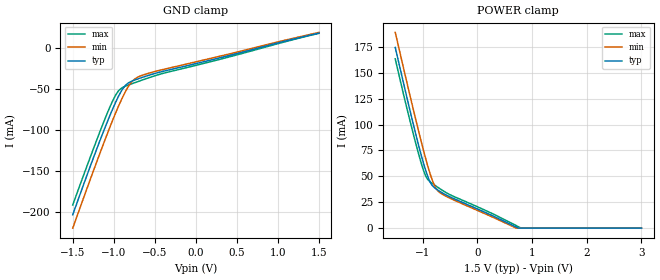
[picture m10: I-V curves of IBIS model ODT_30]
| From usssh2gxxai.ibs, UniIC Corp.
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|   Model ODT_30
[Model]  ODT_30
Model_type Input
Polarity   Non-Inverting
Vinl =   0.60000000V
Vinh =   0.90000000V
C_comp   1.6160pF   1.5840pF   1.6430pF
[Temperature Range]   25.0000   95.0000   -40.0
[Voltage Range]   1.5000V   1.4000V   1.6000V
[GND_clamp]
|Voltage   I(typ)   I(min)   I(max)
-1.5V     -203.9mA   -220.3mA   -191.9mA
-1.18V    -116mA     -131.6mA   -105mA
-1.06V    -85.46mA   -99.88mA   -74.85mA
-980mV    -66.67mA   -79.85mA   -57.74mA
-940mV    -58.23mA   -70.39mA   -51.76mA
-900mV    -50.99mA   -61.49mA   -48.39mA
-860mV    -45.58mA   -53.36mA   -46.49mA
-780mV    -40.23mA   -40.95mA   -43.48mA
-740mV    -38.69mA   -37.28mA   -42.03mA
-660mV    -35.93mA   -33.33mA   -39.16mA
-460mV    -29.78mA   -27.46mA   -32.47mA
1.5V      18.56mA    19.46mA    18.29mA
[POWER_clamp]
|Voltage   I(typ)   I(min)   I(max)
-1.5V     174.4mA    189mA      163.4mA
-1.2V     106.8mA    121.2mA    97.13mA
-1.06V    77.31mA    90.84mA    69.11mA
-980mV    62.01mA    74.31mA    55.2mA
-920mV    51.96mA    62.62mA    48.02mA
-840mV    42.39mA    48.79mA    43.81mA
-760mV    38.13mA    38.9mA     40.77mA
-680mV    35.36mA    34.13mA    37.89mA
-500mV    30.21mA    28.9mA     32.3mA
300mV     11.49mA    10.17mA    13.42mA
749.7mV   0A         NA         NA
3V        0A         0A         0A
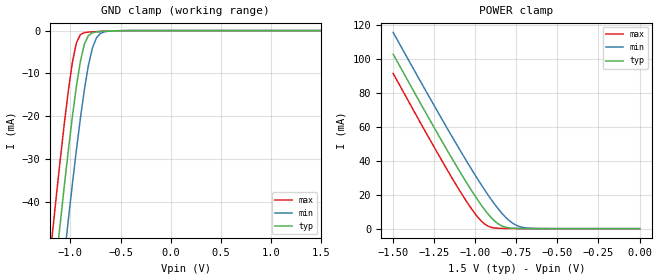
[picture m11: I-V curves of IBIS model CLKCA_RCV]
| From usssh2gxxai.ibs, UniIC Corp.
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|   Model CLKCA_RCV
[Model]  CLKCA_RCV
Model_type Input
Polarity   Non-Inverting
Vinl =   0.60000000V
Vinh =   0.90000000V
C_comp   0.8363pF   0.8073pF   0.8594pF
[Temperature Range]   25.0000   95.0000   -40.0
[Voltage Range]   1.5000V   1.4000V   1.6000V
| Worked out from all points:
|   GND clamp passes 1 mA (typ) near -0.81 V on its own axis
|   POWER clamp passes 1 mA (typ) near -0.82 V on its own axis
[GND_clamp]
|Voltage   I(typ)   I(min)   I(max)
-1.5V     -137.6mA   -154.4mA   -122.8mA
-1.18V    -62.6mA    -79.5mA    -47.6mA
-1.1V     -44.81mA   -61.52mA   -30mA
-1.06V    -36.22mA   -52.75mA   -21.69mA
-1.02V    -27.95mA   -44.18mA   -14.01mA
-940mV    -13.07mA   -27.92mA   -2.891mA
-900mV    -7.188mA   -20.47mA   -945.6uA
-860mV    -3.14mA    -13.76mA   -470.6uA
-780mV    -507.6uA   -4.051mA   -295uA
-740mV    -309.8uA   -1.698mA   -246.6uA
-660mV    -182.5uA   -284.6uA   -158.1uA
1.5V      428.1pA    472.3pA    376.4pA
[POWER_clamp]
|Voltage   I(typ)   I(min)   I(max)
-1.5V     102.9mA    115.8mA    91.58mA
-1.18V    47.75mA    60.71mA    36.22mA
-1.08V    31.38mA    44.19mA    20.1mA
-1V       19.09mA    31.47mA    8.645mA
-940mV    10.82mA    22.44mA    2.495mA
-920mV    8.387mA    19.57mA    1.356mA
-880mV    4.308mA    14.14mA    379.7uA
-840mV    1.685mA    9.283mA    168.9uA
-780mV    312.9uA    3.713mA    93.35uA
-720mV    93.05uA    944.1uA    52.82uA
-660mV    42.22uA    183.2uA    24.02uA
0V        428.1pA    310pA      534pA
